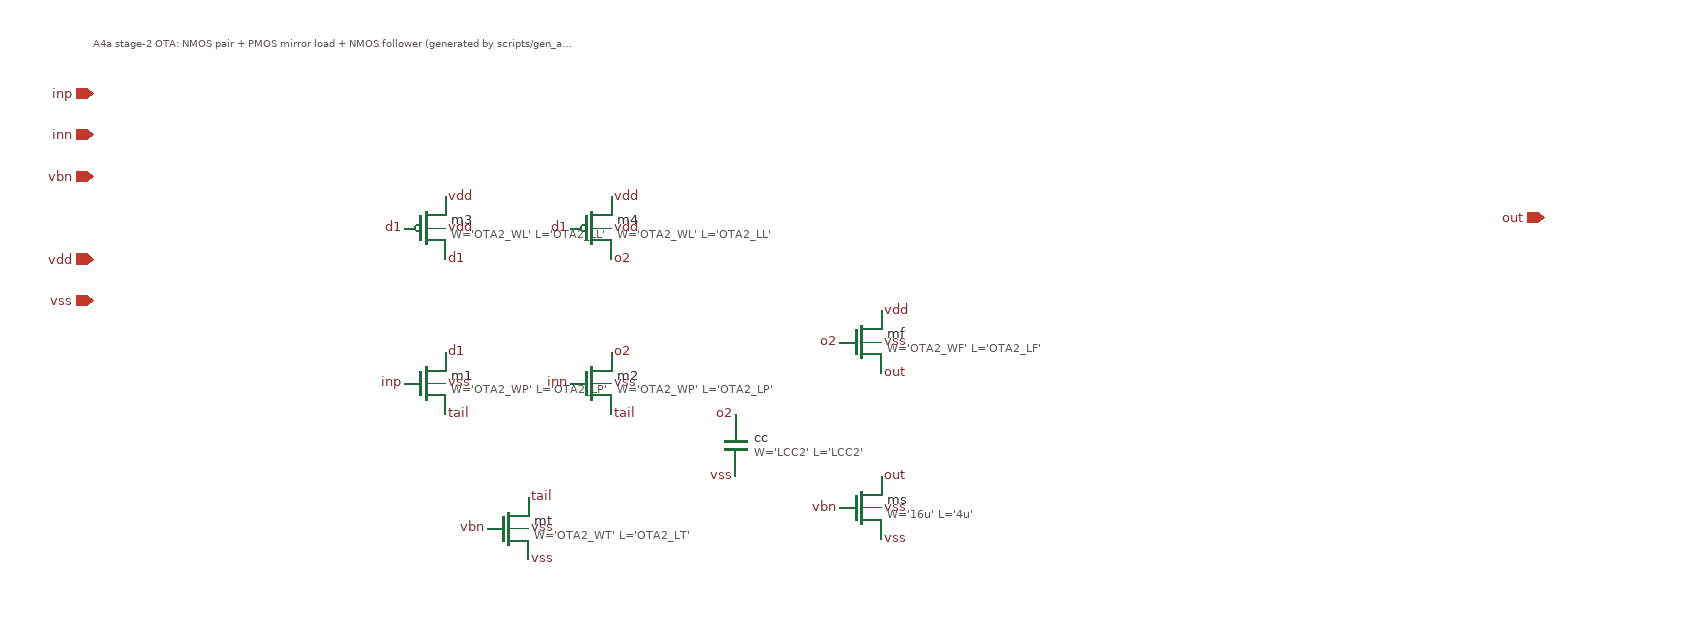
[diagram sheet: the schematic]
v {xschem version=3.4.7 file_version=1.2}
G {}
K {}
V {}
S {}
E {}
C {symbols/nfet_03v3.sym} -300 120 0 0 {name=mt
L='OTA2_LT'
W='OTA2_WT'
nf=1
m='1'
ad='DIFF*OTA2_WT*0.18u'
as='DIFF*OTA2_WT*0.18u'
pd='DIFF*2*(OTA2_WT+0.18u)'
ps='DIFF*2*(OTA2_WT+0.18u)'
nrd=0
nrs=0
sa=0 sb=0 sd=0
model=nfet_03v3
spiceprefix=X}
C {lab_pin.sym} -280 90 0 1 {name=p1 sig_type=std_logic lab=tail}
C {lab_pin.sym} -280 150 0 1 {name=p2 sig_type=std_logic lab=vss}
C {lab_pin.sym} -320 120 0 0 {name=p3 sig_type=std_logic lab=vbn}
C {lab_pin.sym} -280 120 0 1 {name=p4 sig_type=std_logic lab=vss}
C {symbols/nfet_03v3.sym} -380 -20 0 0 {name=m1
L='OTA2_LP'
W='OTA2_WP'
nf=1
m='1'
ad='DIFF*OTA2_WP*0.18u'
as='DIFF*OTA2_WP*0.18u'
pd='DIFF*2*(OTA2_WP+0.18u)'
ps='DIFF*2*(OTA2_WP+0.18u)'
nrd=0
nrs=0
sa=0 sb=0 sd=0
model=nfet_03v3
spiceprefix=X}
C {lab_pin.sym} -360 -50 0 1 {name=p5 sig_type=std_logic lab=d1}
C {lab_pin.sym} -360 10 0 1 {name=p6 sig_type=std_logic lab=tail}
C {lab_pin.sym} -400 -20 0 0 {name=p7 sig_type=std_logic lab=inp}
C {lab_pin.sym} -360 -20 0 1 {name=p8 sig_type=std_logic lab=vss}
C {symbols/nfet_03v3.sym} -220 -20 0 0 {name=m2
L='OTA2_LP'
W='OTA2_WP'
nf=1
m='1'
ad='DIFF*OTA2_WP*0.18u'
as='DIFF*OTA2_WP*0.18u'
pd='DIFF*2*(OTA2_WP+0.18u)'
ps='DIFF*2*(OTA2_WP+0.18u)'
nrd=0
nrs=0
sa=0 sb=0 sd=0
model=nfet_03v3
spiceprefix=X}
C {lab_pin.sym} -200 -50 0 1 {name=p9 sig_type=std_logic lab=o2}
C {lab_pin.sym} -200 10 0 1 {name=p10 sig_type=std_logic lab=tail}
C {lab_pin.sym} -240 -20 0 0 {name=p11 sig_type=std_logic lab=inn}
C {lab_pin.sym} -200 -20 0 1 {name=p12 sig_type=std_logic lab=vss}
C {symbols/pfet_03v3.sym} -380 -170 0 0 {name=m3
L='OTA2_LL'
W='OTA2_WL'
nf=1
m='1'
ad='DIFF*OTA2_WL*0.18u'
as='DIFF*OTA2_WL*0.18u'
pd='DIFF*2*(OTA2_WL+0.18u)'
ps='DIFF*2*(OTA2_WL+0.18u)'
nrd=0
nrs=0
sa=0 sb=0 sd=0
model=pfet_03v3
spiceprefix=X}
C {lab_pin.sym} -360 -200 0 1 {name=p13 sig_type=std_logic lab=vdd}
C {lab_pin.sym} -360 -140 0 1 {name=p14 sig_type=std_logic lab=d1}
C {lab_pin.sym} -400 -170 0 0 {name=p15 sig_type=std_logic lab=d1}
C {lab_pin.sym} -360 -170 0 1 {name=p16 sig_type=std_logic lab=vdd}
C {symbols/pfet_03v3.sym} -220 -170 0 0 {name=m4
L='OTA2_LL'
W='OTA2_WL'
nf=1
m='1'
ad='DIFF*OTA2_WL*0.18u'
as='DIFF*OTA2_WL*0.18u'
pd='DIFF*2*(OTA2_WL+0.18u)'
ps='DIFF*2*(OTA2_WL+0.18u)'
nrd=0
nrs=0
sa=0 sb=0 sd=0
model=pfet_03v3
spiceprefix=X}
C {lab_pin.sym} -200 -200 0 1 {name=p17 sig_type=std_logic lab=vdd}
C {lab_pin.sym} -200 -140 0 1 {name=p18 sig_type=std_logic lab=o2}
C {lab_pin.sym} -240 -170 0 0 {name=p19 sig_type=std_logic lab=d1}
C {lab_pin.sym} -200 -170 0 1 {name=p20 sig_type=std_logic lab=vdd}
C {symbols/nfet_03v3.sym} 40 -60 0 0 {name=mf
L='OTA2_LF'
W='OTA2_WF'
nf=1
m='1'
ad='DIFF*OTA2_WF*0.18u'
as='DIFF*OTA2_WF*0.18u'
pd='DIFF*2*(OTA2_WF+0.18u)'
ps='DIFF*2*(OTA2_WF+0.18u)'
nrd=0
nrs=0
sa=0 sb=0 sd=0
model=nfet_03v3
spiceprefix=X}
C {lab_pin.sym} 60 -90 0 1 {name=p21 sig_type=std_logic lab=vdd}
C {lab_pin.sym} 60 -30 0 1 {name=p22 sig_type=std_logic lab=out}
C {lab_pin.sym} 20 -60 0 0 {name=p23 sig_type=std_logic lab=o2}
C {lab_pin.sym} 60 -60 0 1 {name=p24 sig_type=std_logic lab=vss}
C {symbols/nfet_03v3.sym} 40 100 0 0 {name=ms
L='4u'
W='16u'
nf=1
m='BM_KSF'
ad='DIFF*16u*0.18u'
as='DIFF*16u*0.18u'
pd='DIFF*2*(16u+0.18u)'
ps='DIFF*2*(16u+0.18u)'
nrd=0
nrs=0
sa=0 sb=0 sd=0
model=nfet_03v3
spiceprefix=X}
C {lab_pin.sym} 60 70 0 1 {name=p25 sig_type=std_logic lab=out}
C {lab_pin.sym} 60 130 0 1 {name=p26 sig_type=std_logic lab=vss}
C {lab_pin.sym} 20 100 0 0 {name=p27 sig_type=std_logic lab=vbn}
C {lab_pin.sym} 60 100 0 1 {name=p28 sig_type=std_logic lab=vss}
C {symbols/cap_mim_2f0fF.sym} -80 40 0 0 {name=cc
W='LCC2'
L='LCC2'
model=cap_mim_2f0_m2m3_noshield
spiceprefix=X
m=1}
C {lab_pin.sym} -80 10 3 0 {name=p29 sig_type=std_logic lab=o2}
C {lab_pin.sym} -80 70 1 0 {name=p30 sig_type=std_logic lab=vss}
C {ipin.sym} -700 -300 0 0 {name=io31 lab=inp}
C {ipin.sym} -700 -260 0 0 {name=io32 lab=inn}
C {ipin.sym} -700 -220 0 0 {name=io33 lab=vbn}
C {opin.sym} 700 -180 0 1 {name=io34 lab=out}
C {iopin.sym} -700 -140 0 0 {name=io35 lab=vdd}
C {iopin.sym} -700 -100 0 0 {name=io36 lab=vss}
T {A4a stage-2 OTA: NMOS pair + PMOS mirror load + NMOS follower (generated by scripts/gen_a4a_sch.py). Sizes = spice/afe_params.spice.} -700 -360 0 0 0.3 0.3 {}
